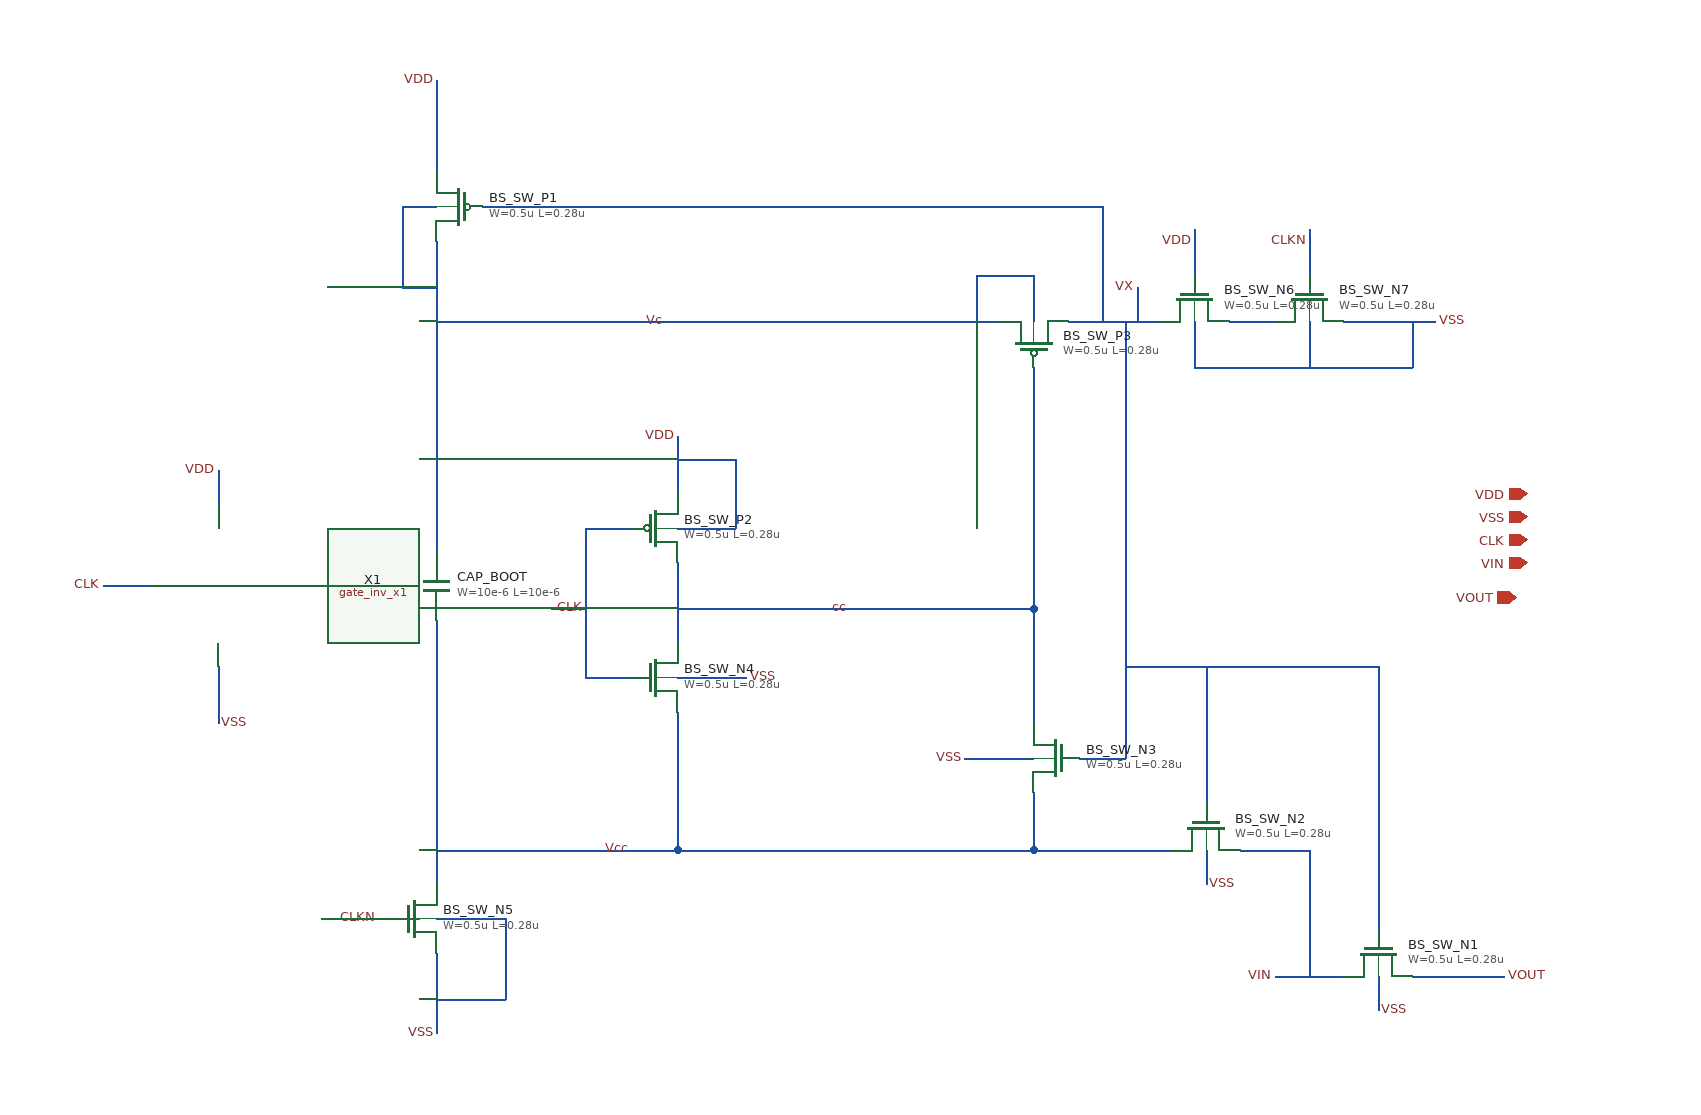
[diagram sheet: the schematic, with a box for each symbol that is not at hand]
v {xschem version=3.4.8RC file_version=1.3}
G {}
K {}
V {}
S {}
F {}
E {}
N 560 -490 560 -420 {lab=cc}
N 1040 -700 1080 -700 {lab=#net1}
N 1140 -700 1220 -700 {lab=VSS}
N 1110 -780 1110 -740 {lab=CLKN}
N 1010 -780 1010 -740 {lab=VDD}
N 900 -700 980 -700 {lab=VX}
N 1100 -130 1140 -130 {lab=VIN}
N 1170 -210 1170 -170 {lab=VX}
N 1020 -320 1020 -280 {lab=VX}
N 1170 -130 1170 -100 {lab=VSS}
N 1020 -240 1020 -210 {lab=VSS}
N 560 -450 870 -450 {lab=cc}
N 870 -360 870 -350 {lab=cc}
N 560 -360 560 -240 {lab=Vcc}
N 560 -240 870 -240 {lab=Vcc}
N 870 -290 870 -240 {lab=Vcc}
N 870 -450 870 -360 {lab=cc}
N 350 -150 350 -80 {lab=VSS}
N 350 -660 350 -500 {lab=Vc}
N 350 -440 350 -280 {lab=Vcc}
N 350 -280 350 -210 {lab=Vcc}
N 350 -770 350 -660 {lab=Vc}
N 350 -910 350 -830 {lab=VDD}
N 390 -800 930 -800 {lab=VX}
N 930 -800 930 -700 {lab=VX}
N 320 -800 350 -800 {lab=Vc}
N 320 -800 320 -730 {lab=Vc}
N 320 -730 350 -730 {lab=Vc}
N 350 -700 840 -700 {lab=Vc}
N 350 -180 410 -180 {lab=VSS}
N 410 -180 410 -110 {lab=VSS}
N 350 -110 410 -110 {lab=VSS}
N 250 -180 310 -180 {lab=CLKN}
N 480 -390 520 -390 {lab=CLK}
N 480 -520 520 -520 {lab=CLK}
N 480 -520 480 -390 {lab=CLK}
N 450 -450 480 -450 {lab=CLK}
N 510 -240 560 -240 {lab=Vcc}
N 350 -240 510 -240 {lab=Vcc}
N 560 -600 560 -550 {lab=VDD}
N 560 -390 620 -390 {lab=VSS}
N 560 -520 610 -520 {lab=VDD}
N 610 -580 610 -520 {lab=VDD}
N 560 -580 610 -580 {lab=VDD}
N 810 -320 870 -320 {lab=VSS}
N 870 -740 870 -700 {lab=Vc}
N 820 -740 870 -740 {lab=Vc}
N 820 -740 820 -700 {lab=Vc}
N 1010 -700 1010 -660 {lab=VSS}
N 1010 -660 1200 -660 {lab=VSS}
N 1200 -700 1200 -660 {lab=VSS}
N 1110 -700 1110 -660 {lab=VSS}
N 950 -700 950 -320 {lab=VX}
N 950 -400 1030 -400 {lab=VX}
N 1030 -400 1130 -400 {lab=VX}
N 1200 -130 1280 -130 {lab=VOUT}
N 160 -400 160 -350 {lab=VSS}
N 160 -570 160 -540 {lab=VDD}
N 60 -470 100 -470 {lab=CLK}
N 240 -470 280 -470 {lab=CLKN}
N 930 -320 950 -320 {lab=VX}
N 910 -320 930 -320 {lab=VX}
N 870 -240 1000 -240 {lab=Vcc}
N 1170 -400 1170 -210 {lab=VX}
N 1130 -400 1170 -400 {lab=VX}
N 1080 -130 1100 -130 {lab=VIN}
N 1050 -240 1110 -240 {lab=VIN}
N 1110 -240 1110 -130 {lab=VIN}
N 1020 -400 1020 -320 {lab=VX}
N 960 -730 960 -700 {lab=VX}
N 870 -470 870 -450 {lab=cc}
N 870 -660 870 -470 {lab=cc}
C {iopin.sym} 1300 -510 0 0 {name=p2 lab=CLK}
C {iopin.sym} 1300 -530 0 0 {name=p3 lab=VSS}
C {iopin.sym} 1300 -550 0 0 {name=p4 lab=VDD}
C {iopin.sym} 1290 -460 0 0 {name=p5 lab=VOUT}
C {iopin.sym} 1300 -490 0 0 {name=p6 lab=VIN}
C {lab_wire.sym} 350 -910 0 0 {name=p7 sig_type=std_logic lab=VDD}
C {lab_wire.sym} 1010 -770 0 0 {name=p8 sig_type=std_logic lab=VDD}
C {lab_wire.sym} 1220 -700 0 1 {name=p10 sig_type=std_logic lab=VSS}
C {lab_wire.sym} 1280 -130 0 1 {name=p11 sig_type=std_logic lab=VOUT}
C {lab_wire.sym} 1080 -130 2 1 {name=p12 sig_type=std_logic lab=VIN}
C {lab_wire.sym} 1020 -210 2 0 {name=p14 sig_type=std_logic lab=VSS}
C {lab_wire.sym} 810 -320 2 1 {name=p15 sig_type=std_logic lab=VSS}
C {lab_wire.sym} 350 -80 2 1 {name=p16 sig_type=std_logic lab=VSS}
C {lab_wire.sym} 620 -390 2 0 {name=p17 sig_type=std_logic lab=VSS}
C {lab_wire.sym} 560 -600 0 0 {name=p20 sig_type=std_logic lab=VDD}
C {lab_wire.sym} 160 -350 2 0 {name=p21 sig_type=std_logic lab=VSS}
C {lab_wire.sym} 60 -470 0 0 {name=p22 sig_type=std_logic lab=CLK}
C {lab_wire.sym} 160 -570 0 0 {name=p23 sig_type=std_logic lab=VDD}
C {lab_wire.sym} 1110 -770 0 0 {name=p26 sig_type=std_logic lab=CLKN
}
C {symbols/nfet_03v3.sym} 1110 -720 3 1 {name=BS_SW_N7
L=0.28u
W=0.5u
nf=1
m=2
ad="'int((nf+1)/2) * W/nf * 0.18u'"
pd="'2*int((nf+1)/2) * (W/nf + 0.18u)'"
as="'int((nf+2)/2) * W/nf * 0.18u'"
ps="'2*int((nf+2)/2) * (W/nf + 0.18u)'"
nrd="'0.18u / W'" nrs="'0.18u / W'"
sa=0 sb=0 sd=0
model=nfet_03v3
spiceprefix=X
}
C {symbols/nfet_03v3.sym} 890 -320 0 1 {name=BS_SW_N3
L=0.28u
W=0.5u
nf=1
m=1
ad="'int((nf+1)/2) * W/nf * 0.18u'"
pd="'2*int((nf+1)/2) * (W/nf + 0.18u)'"
as="'int((nf+2)/2) * W/nf * 0.18u'"
ps="'2*int((nf+2)/2) * (W/nf + 0.18u)'"
nrd="'0.18u / W'" nrs="'0.18u / W'"
sa=0 sb=0 sd=0
model=nfet_03v3
spiceprefix=X
}
C {symbols/pfet_03v3.sym} 870 -680 3 0 {name=BS_SW_P3
L=0.28u
W=0.5u
nf=1
m=2
ad="'int((nf+1)/2) * W/nf * 0.18u'"
pd="'2*int((nf+1)/2) * (W/nf + 0.18u)'"
as="'int((nf+2)/2) * W/nf * 0.18u'"
ps="'2*int((nf+2)/2) * (W/nf + 0.18u)'"
nrd="'0.18u / W'" nrs="'0.18u / W'"
sa=0 sb=0 sd=0
model=pfet_03v3
spiceprefix=X
}
C {symbols/nfet_03v3.sym} 1010 -720 3 1 {name=BS_SW_N6
L=0.28u
W=0.5u
nf=1
m=2
ad="'int((nf+1)/2) * W/nf * 0.18u'"
pd="'2*int((nf+1)/2) * (W/nf + 0.18u)'"
as="'int((nf+2)/2) * W/nf * 0.18u'"
ps="'2*int((nf+2)/2) * (W/nf + 0.18u)'"
nrd="'0.18u / W'" nrs="'0.18u / W'"
sa=0 sb=0 sd=0
model=nfet_03v3
spiceprefix=X
}
C {lab_wire.sym} 960 -730 0 0 {name=p1 sig_type=std_logic lab=VX}
C {lab_wire.sym} 710 -450 0 0 {name=p24 sig_type=std_logic lab=cc}
C {symbols/pfet_03v3.sym} 370 -800 0 1 {name=BS_SW_P1
L=0.28u
W=0.5u
nf=1
m=2
ad="'int((nf+1)/2) * W/nf * 0.18u'"
pd="'2*int((nf+1)/2) * (W/nf + 0.18u)'"
as="'int((nf+2)/2) * W/nf * 0.18u'"
ps="'2*int((nf+2)/2) * (W/nf + 0.18u)'"
nrd="'0.18u / W'" nrs="'0.18u / W'"
sa=0 sb=0 sd=0
model=pfet_03v3
spiceprefix=X
}
C {lab_wire.sym} 550 -700 0 0 {name=p25 sig_type=std_logic lab=Vc}
C {lab_wire.sym} 520 -240 0 0 {name=p27 sig_type=std_logic lab=Vcc}
C {lab_wire.sym} 1170 -100 2 0 {name=p13 sig_type=std_logic lab=VSS}
C {lab_wire.sym} 280 -470 0 1 {name=p9 sig_type=std_logic lab=CLKN
}
C {lab_wire.sym} 480 -450 0 0 {name=p19 sig_type=std_logic lab=CLK}
C {symbols/nfet_03v3.sym} 1170 -150 1 0 {name=BS_SW_N1
L=0.28u
W=0.5u
nf=1
m=3
ad="'int((nf+1)/2) * W/nf * 0.18u'"
pd="'2*int((nf+1)/2) * (W/nf + 0.18u)'"
as="'int((nf+2)/2) * W/nf * 0.18u'"
ps="'2*int((nf+2)/2) * (W/nf + 0.18u)'"
nrd="'0.18u / W'" nrs="'0.18u / W'"
sa=0 sb=0 sd=0
model=nfet_03v3
spiceprefix=X
}
C {symbols/nfet_03v3.sym} 1020 -260 1 0 {name=BS_SW_N2
L=0.28u
W=0.5u
nf=1
m=1
ad="'int((nf+1)/2) * W/nf * 0.18u'"
pd="'2*int((nf+1)/2) * (W/nf + 0.18u)'"
as="'int((nf+2)/2) * W/nf * 0.18u'"
ps="'2*int((nf+2)/2) * (W/nf + 0.18u)'"
nrd="'0.18u / W'" nrs="'0.18u / W'"
sa=0 sb=0 sd=0
model=nfet_03v3
spiceprefix=X
}
C {symbols/nfet_03v3.sym} 330 -180 0 0 {name=BS_SW_N5
L=0.28u
W=0.5u
nf=1
m=1
ad="'int((nf+1)/2) * W/nf * 0.18u'"
pd="'2*int((nf+1)/2) * (W/nf + 0.18u)'"
as="'int((nf+2)/2) * W/nf * 0.18u'"
ps="'2*int((nf+2)/2) * (W/nf + 0.18u)'"
nrd="'0.18u / W'" nrs="'0.18u / W'"
sa=0 sb=0 sd=0
model=nfet_03v3
spiceprefix=X
}
C {symbols/nfet_03v3.sym} 540 -390 0 0 {name=BS_SW_N4
L=0.28u
W=0.5u
nf=1
m=1
ad="'int((nf+1)/2) * W/nf * 0.18u'"
pd="'2*int((nf+1)/2) * (W/nf + 0.18u)'"
as="'int((nf+2)/2) * W/nf * 0.18u'"
ps="'2*int((nf+2)/2) * (W/nf + 0.18u)'"
nrd="'0.18u / W'" nrs="'0.18u / W'"
sa=0 sb=0 sd=0
model=nfet_03v3
spiceprefix=X
}
C {lab_wire.sym} 300 -180 0 0 {name=p28 sig_type=std_logic lab=CLKN
}
C {symbols/pfet_03v3.sym} 540 -520 0 0 {name=BS_SW_P2
L=0.28u
W=0.5u
nf=1
m=2
ad="'int((nf+1)/2) * W/nf * 0.18u'"
pd="'2*int((nf+1)/2) * (W/nf + 0.18u)'"
as="'int((nf+2)/2) * W/nf * 0.18u'"
ps="'2*int((nf+2)/2) * (W/nf + 0.18u)'"
nrd="'0.18u / W'" nrs="'0.18u / W'"
sa=0 sb=0 sd=0
model=pfet_03v3
spiceprefix=X
}
C {symbols/cap_mim_2f0fF.sym} 350 -470 0 0 {name=CAP_BOOT
W=10e-6
L=10e-6
model=cap_mim_2f0fF
spiceprefix=X
m=1}
C {designs/sar_adc/digital/gate_inv_x1/xschem/gate_inv_x1.sym} 180 -450 0 0 {name=X1}
